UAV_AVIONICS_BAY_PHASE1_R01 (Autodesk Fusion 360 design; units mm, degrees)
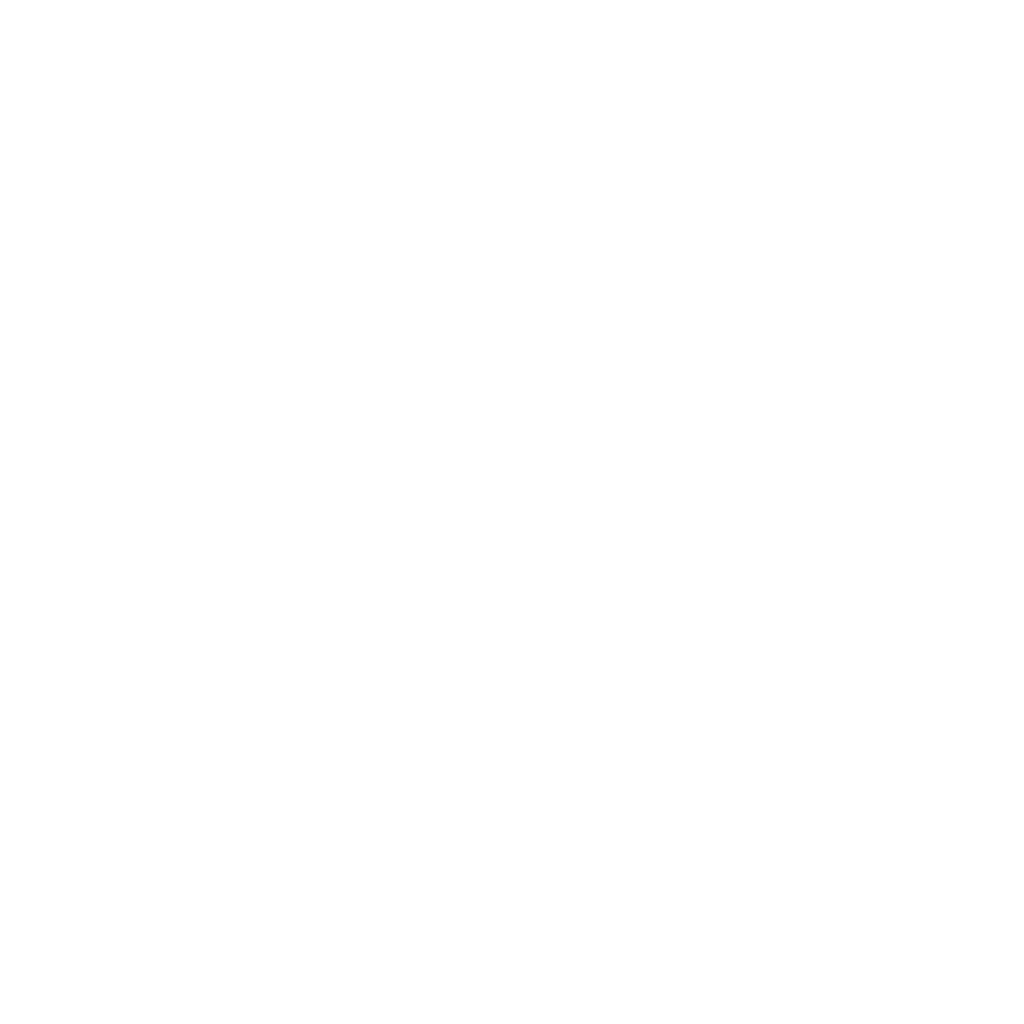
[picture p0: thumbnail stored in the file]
part number: 2026-11-23-22-58-29-359
part number: 2026-11-23-22-58-29-674
part number: 2026-11-23-22-58-29-703
part number: 2026-11-23-22-58-29-715
part number: 2026-11-23-22-58-29-725
part number: 2026-11-23-22-58-29-736
part number: 2026-11-23-22-58-29-745
part number: 2026-11-23-22-58-29-755
part number: 2026-11-23-22-58-29-765
parameter "BAY_LENGTH" = 180 comment "[Assumption] Concept avionics bay overall outer length (X)"
parameter "BAY_WIDTH" = 75 comment "[Assumption] Concept avionics bay overall outer width (Y)"
parameter "BAY_HEIGHT" = 45 comment "[Assumption] Concept avionics bay overall outer height (Z)"
parameter "TRAY_FLANGE_H" = 22 comment "[Preliminary] Base tray perimeter upward flange height"
parameter "COVER_SKIRT_H" = 10 comment "[Preliminary] Top cover downward perimeter skirt height"
parameter "FORWARD_ZONE_END_X" = 95 comment "[Preliminary] X-boundary separating battery zone and aft deck"
parameter "HATCH_LENGTH" = 92 comment "[Preliminary] Service access hatch opening length"
parameter "HATCH_WIDTH" = 54 comment "[Preliminary] Service access hatch opening width"
parameter "T_BASE_TRAY" = 1 comment "[Preliminary] Main folded base tray thickness"
parameter "T_TOP_COVER" = 0.8 comment "[Preliminary] Removable top cover thickness"
parameter "T_ACCESS_HATCH" = 0.8 comment "[Preliminary] Service access hatch thickness"
parameter "T_SIDE_RAIL" = 1 comment "[Preliminary] Left and right side support rails thickness"
parameter "T_BULKHEAD" = 1 comment "[Preliminary] Front, rear, and connector bulkheads thickness"
parameter "T_EQUIP_DECK" = 1 comment "[Preliminary] Removable internal equipment deck thickness"
parameter "T_BRACKET" = 1 comment "[Preliminary] Structural and retention brackets thickness"
parameter "T_CABLE_CH" = 0.8 comment "[Preliminary] Cable routing channel and clamp thickness"
parameter "BEND_R_1_0" = 1 comment "[Preliminary] Inside bend radius for 1.0 mm Al 5052-H32"
parameter "BEND_R_0_8" = 0.8 comment "[Preliminary] Inside bend radius for 0.8 mm Al 5052-H32"
parameter "RELIEF_W_1_0" = 1.5 comment "[Preliminary] Bend relief width for 1.0 mm sheet"
parameter "RELIEF_D_1_0" = 2.5 comment "[Preliminary] Bend relief depth for 1.0 mm sheet"
parameter "RELIEF_W_0_8" = 1.2 comment "[Preliminary] Bend relief width for 0.8 mm sheet"
parameter "RELIEF_D_0_8" = 2.1 comment "[Preliminary] Bend relief depth for 0.8 mm sheet"
parameter "HOLE_CLR_M2_0" = 2.2 comment "[Preliminary] M2.0 medium clearance hole diameter"
parameter "HOLE_CLR_M2_5" = 2.7 comment "[Preliminary] M2.5 medium clearance hole diameter"
parameter "HOLE_CLR_M3_0" = 3.4 comment "[Preliminary] M3.0 medium clearance hole diameter"
parameter "HEAD_DIA_M2_0" = 3.8 comment "[Preliminary] ISO 4762/7380 M2.0 head diameter"
parameter "HEAD_DIA_M2_5" = 4.5 comment "[Preliminary] ISO 4762/7380 M2.5 head diameter"
parameter "STANDOFF_DECK_H" = 6 comment "[Preliminary] Under-deck plenum standoff height"
parameter "STANDOFF_PCB_H" = 4 comment "[Preliminary] PCB mounting standoff height"
parameter "ISO_PAD_THICK" = 2 comment "[Preliminary] Battery elastomer isolation pad thickness"
parameter "CLR_EQUIP_WALL" = 2 comment "[Preliminary] Minimum clearance between electronics and walls"
parameter "CLR_COMPONENT" = 1.5 comment "[Preliminary] General minimum clearance between adjacent parts"
parameter "CLR_SLIP_FIT" = 0.25 comment "[Preliminary] Per-side slip clearance for nested sheet metal parts"
parameter "CLR_COVER_FIT" = 0.3 comment "[Preliminary] Per-side clearance between cover skirt and chassis"
parameter "CLR_HATCH_GAP" = 0.5 comment "[Preliminary] Perimeter gap around removable service hatch"
parameter "d37" = 2
parameter "d38" = 1
parameter "d39" = 0.8
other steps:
create_component "CreateComponent1"
create_component "CreateComponent2"
create_component "CreateComponent3"
create_component "CreateComponent4"
create_component "CreateComponent5"
create_component "CreateComponent6"
create_component "CreateComponent7"
create_component "CreateComponent8"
